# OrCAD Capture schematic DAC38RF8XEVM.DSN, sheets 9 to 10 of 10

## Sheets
9 SHEET 10 - POWER SUPPLIES: size B; title: POWER SUPPLIES
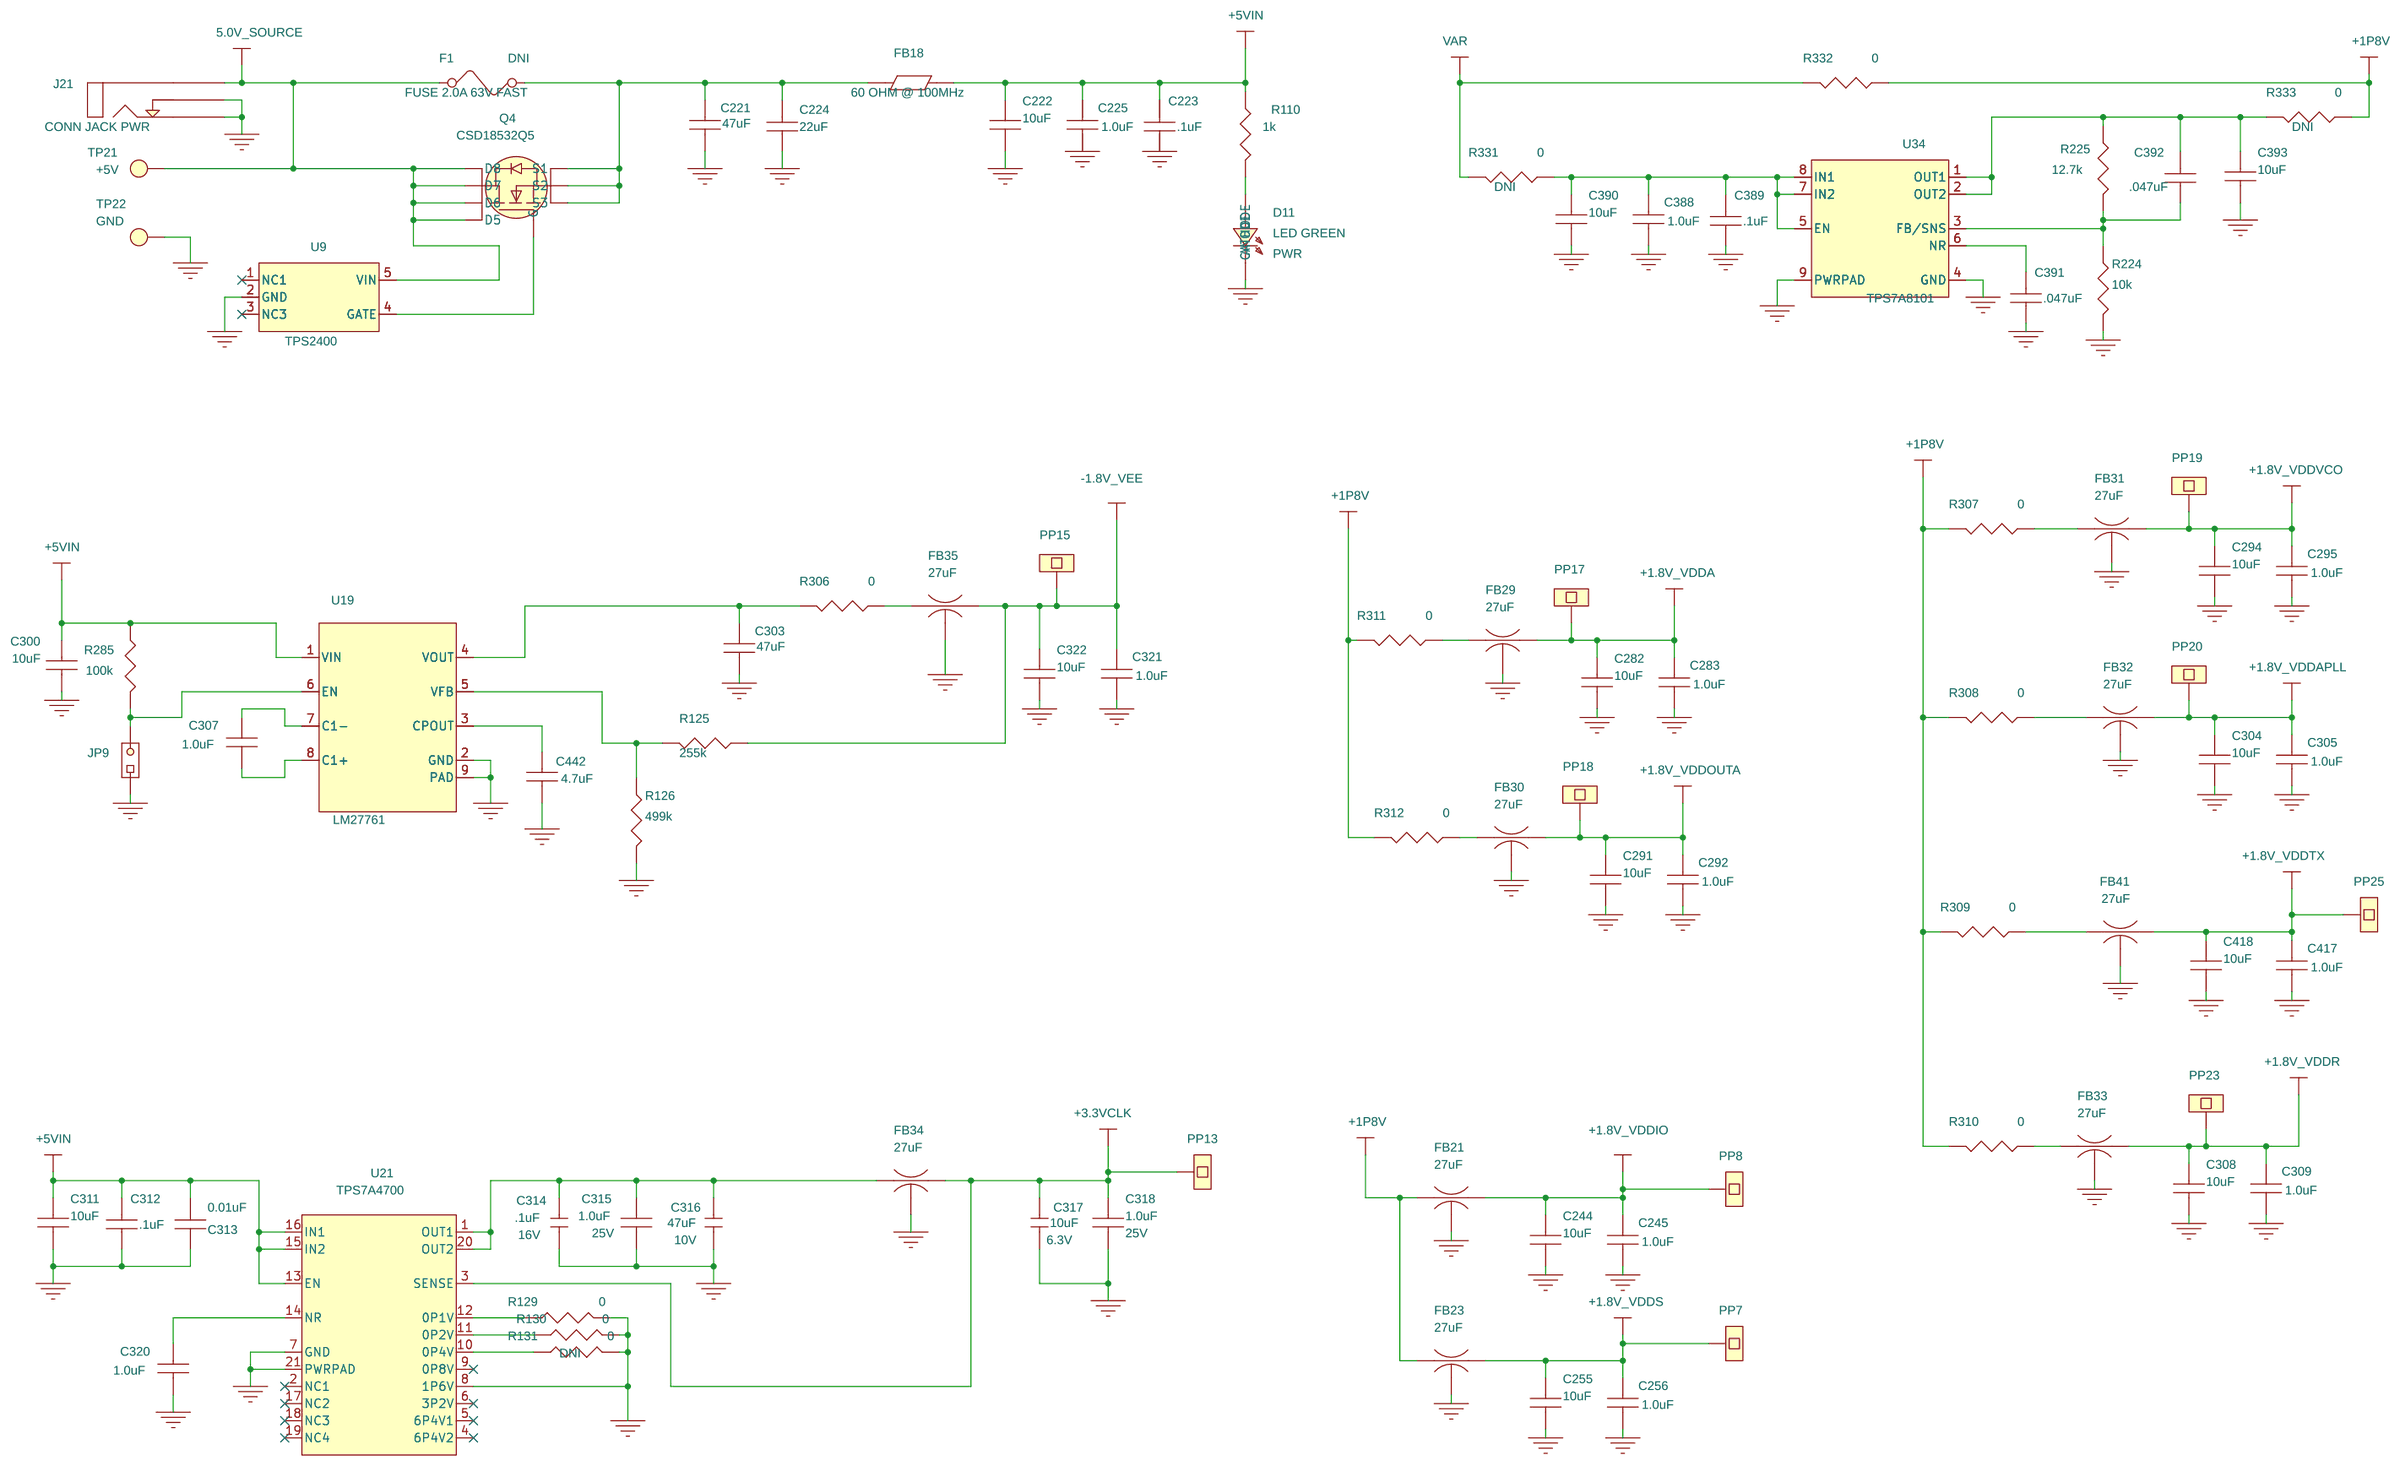
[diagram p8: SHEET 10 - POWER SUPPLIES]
10 SHEET 07 - USB I/F: size B; title: USB INTERFACE

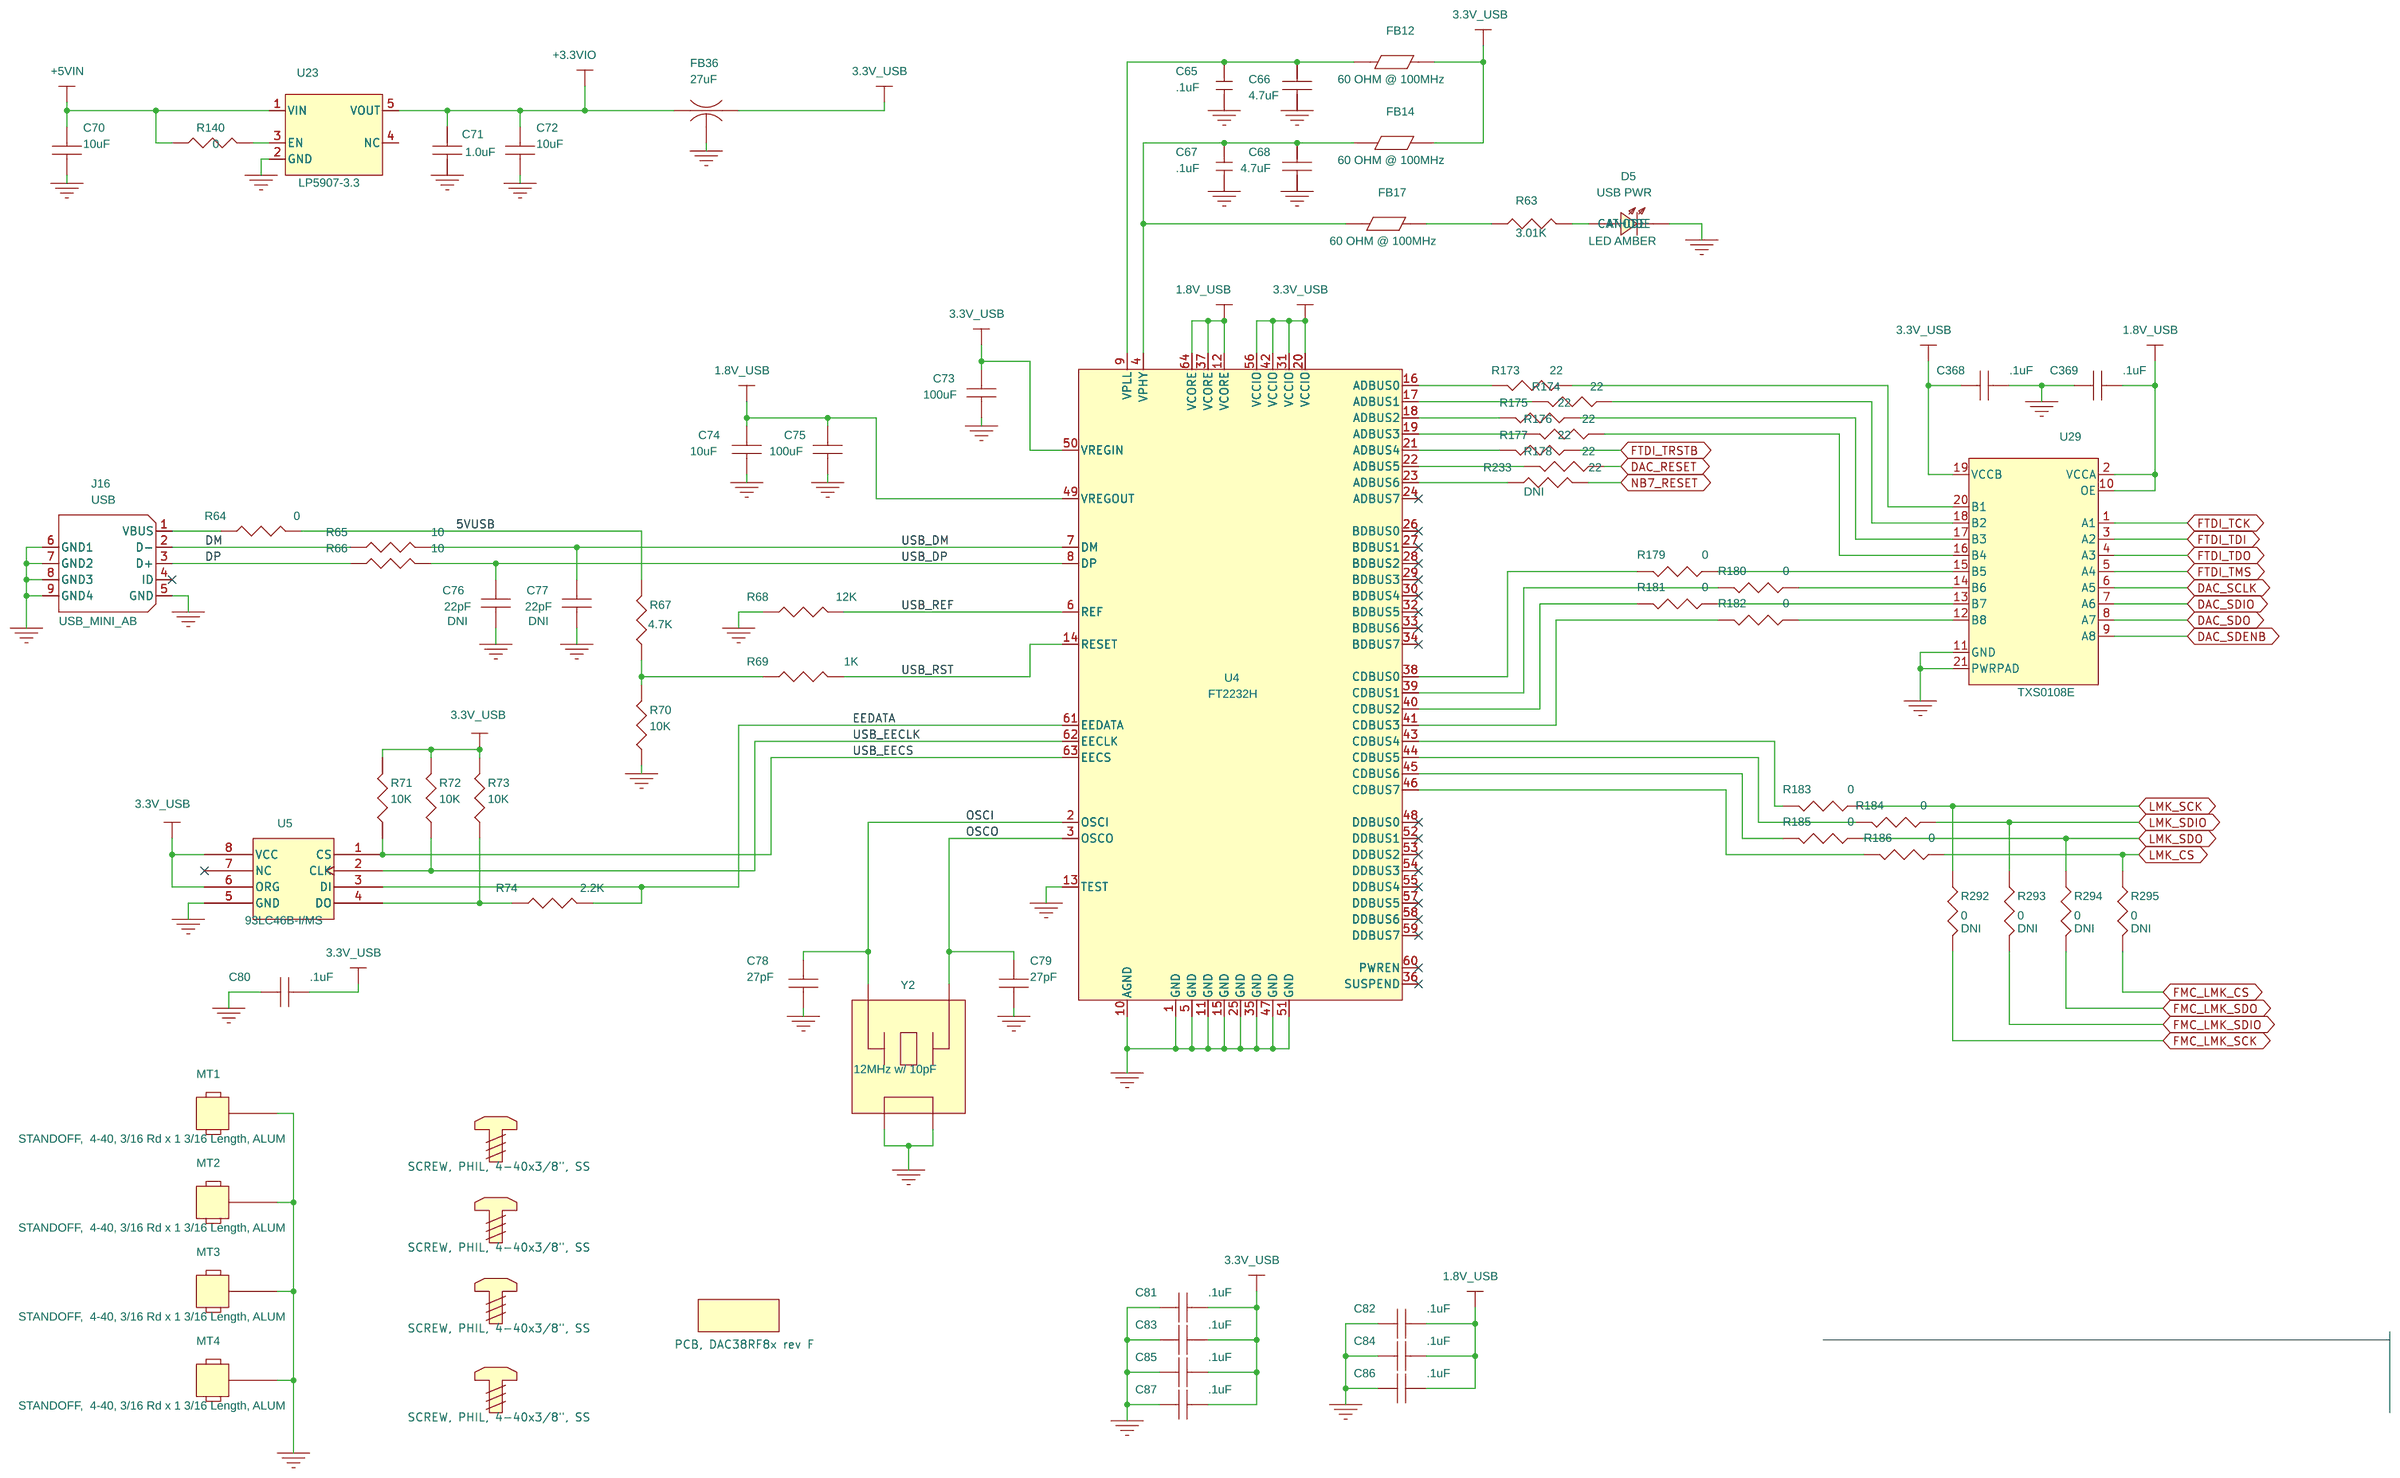
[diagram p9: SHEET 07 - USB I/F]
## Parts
sheet SHEET 07 - USB I/F
C65  .1uF  [0402]
C66  4.7uF  [0603]
C67  .1uF  [0402]
C68  4.7uF  [0603]
C70  10uF  [0805]
C71  1.0uF  [0603]
C72  10uF  [0805]
C73  100uF  [1206]
C74  10uF  [1206]
C75  100uF  [1206]
C76  22pF  [0402]
C77  22pF  [0402]
C78  27pF  [0402]
C79  27pF  [0402]
C80  .1uF  [0402]
C81  .1uF  [0402]
C82  .1uF  [0402]
C83  .1uF  [0402]
C84  .1uF  [0402]
C85  .1uF  [0402]
C86  .1uF  [0402]
C87  .1uF  [0402]
C368  .1uF  [0402]
C369  .1uF  [0402]
D5  LED AMBER  [LED_1206]
FB12  60 OHM @ 100MHz  [1206]
FB14  60 OHM @ 100MHz  [1206]
FB17  60 OHM @ 100MHz  [1206]
FB36  27uF  [1206_BEAD_NFM31P]
J16  USB_MINI_AB  [CON_SMRT_USBMINI_AB_F_mod]
MT1  STANDOFF,  4-40, 3/16 Rd x 1 3/16 Length, ALUM  [MFG125_PLATED]
MT2  STANDOFF,  4-40, 3/16 Rd x 1 3/16 Length, ALUM  [MFG125_PLATED]
MT3  STANDOFF,  4-40, 3/16 Rd x 1 3/16 Length, ALUM  [MFG125_PLATED]
MT4  STANDOFF,  4-40, 3/16 Rd x 1 3/16 Length, ALUM  [MFG125_PLATED]
R63  3.01K  [0402]
R64  0  [0603]
R65  10  [0402]
R66  10  [0402]
R67  4.7K  [0402]
R68  12K  [0402]
R69  1K  [0402]
R70  10K  [0402]
R71  10K  [0402]
R72  10K  [0402]
R73  10K  [0402]
R74  2.2K  [0402]
R140  0  [0402]
R173  22  [0402]
R174  22  [0402]
R175  22  [0402]
R176  22  [0402]
R177  22  [0402]
R178  22  [0402]
R179  0  [0402]
R180  0  [0402]
R181  0  [0402]
R182  0  [0402]
R183  0  [0402]
R184  0  [0402]
R185  0  [0402]
R186  0  [0402]
R233  22  [0402]
R292  0  [0402]
R293  0  [0402]
R294  0  [0402]
R295  0  [0402]
U4  FT2232H  [LQFP_64_402x402_20]
U5  93LC46B-I/MS  [MSOP_8_118X118_26]
U23  LP5907-3.3  [DBV5]
U29  TXS0108E  [QFN_20_183x144_RGY]
Y2  12MHz w/ 10pF  [XTAL_4_SM_130X102]
Z_BOARD1  PCB, DAC38RF8x rev F
Z_SCREW1  SCREW, PHIL, 4-40x3/8", SS
Z_SCREW2  SCREW, PHIL, 4-40x3/8", SS
Z_SCREW3  SCREW, PHIL, 4-40x3/8", SS
Z_SCREW4  SCREW, PHIL, 4-40x3/8", SS
sheet SHEET 10 - POWER SUPPLIES
C221  47uF  [1210]
C222  10uF  [0805]
C223  .1uF  [0402]
C224  22uF  [1206]
C225  1.0uF  [0603]
C244  10uF  [0805]
C245  1.0uF  [0603]
C255  10uF  [0805]
C256  1.0uF  [0603]
C282  10uF  [0805]
C283  1.0uF  [0603]
C291  10uF  [0805]
C292  1.0uF  [0603]
C294  10uF  [0805]
C295  1.0uF  [0603]
C300  10uF  [0805]
C303  47uF  [1210]
C304  10uF  [0805]
C305  1.0uF  [0603]
C307  1.0uF  [0603]
C308  10uF  [0805]
C309  1.0uF  [0603]
C311  10uF  [0805]
C312  .1uF  [0402]
C313  0.01uF  [0402]
C314  .1uF  [0402]
C315  1.0uF  [0603]
C316  47uF  [1210]
C317  10uF  [0805]
C318  1.0uF  [0603]
C320  1.0uF  [0603]
C321  1.0uF  [0603]
C322  10uF  [0805]
C388  1.0uF  [0603]
C389  .1uF  [0402]
C390  10uF  [0805]
C391  .047uF  [0402]
C392  .047uF  [0402]
C393  10uF  [0805]
C417  1.0uF  [0603]
C418  10uF  [0805]
C442  4.7uF  [0603]
D11  LED GREEN  [LED_1206]
F1  FUSE 2.0A 63V FAST  [1206]
FB18  60 OHM @ 100MHz  [1206]
FB21  27uF  [1206_BEAD_NFM31P]
FB23  27uF  [1206_BEAD_NFM31P]
FB29  27uF  [1206_BEAD_NFM31P]
FB30  27uF  [1206_BEAD_NFM31P]
FB31  27uF  [1206_BEAD_NFM31P]
FB32  27uF  [1206_BEAD_NFM31P]
FB33  27uF  [1206_BEAD_NFM31P]
FB34  27uF  [1206_BEAD_NFM31P]
FB35  27uF  [1206_BEAD_NFM31P]
FB41  27uF  [1206_BEAD_NFM31P]
J21  CONN JACK PWR  [CON_RAPC722_JACK_THVT_3]
JP9  HEADER_1x2_100_430L  [HDR_THVT_1x2_100_M]
PP7  PROBE POINT  [PROBE_POINT_22PAD]
PP8  PROBE POINT  [PROBE_POINT_22PAD]
PP13  PROBE POINT  [PROBE_POINT_22PAD]
PP15  PROBE POINT  [PROBE_POINT_22PAD]
PP17  PROBE POINT  [PROBE_POINT_22PAD]
PP18  PROBE POINT  [PROBE_POINT_22PAD]
PP19  PROBE POINT  [PROBE_POINT_22PAD]
PP20  PROBE POINT  [PROBE_POINT_22PAD]
PP23  PROBE POINT  [PROBE_POINT_22PAD]
PP25  PROBE POINT  [PROBE_POINT_22PAD]
Q4  CSD18532Q5  [SON_Q5B_8]
R110  1k  [0402]
R125  255k  [0402]
R126  499k  [0402]
R129  0  [0402]
R130  0  [0402]
R131  0  [0402]
R224  10k  [0402]
R225  12.7k  [0402]
R285  100k  [0402]
R306  0  [0805]
R307  0  [0805]
R308  0  [0805]
R309  0  [0805]
R310  0  [0805]
R311  0  [0805]
R312  0  [0805]
R331  0  [0805]
R332  0  [0805]
R333  0  [0805]
TP21  Testloop_Red  [testpoint_62dia]
TP22  Testloop_Black  [testpoint_62dia]
U9  TPS2400  [DBV5]
U19  LM27761  [SON_DSG_8]
U21  TPS7A4700  [qfn20_rgw_p65pitch]
U34  TPS7A8101  [SON_DRB_8]

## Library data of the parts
C65 C67 C314 = CAP0603: Mfr_Name: MURATA; Mfr_Part_Number: GRM155R71C104KA88D; TOL: 10%; Voltage: 16V
C66 C68 C442 = CAP_NP_0: Mfr_Name: Kemet; Mfr_Part_Number: C0603C475K8PACTU; TOL: 10%; VOLTAGE: 10V
C70 C72 C222 C244 C255 C282 C291 C294 C300 C304 C308 C322 C390 C393 C418 = CAP_NP_1: Mfr_Name: SAMSUNG; Mfr_Part_Number: CL21B106KOQNNNE; TOL: 10%; VOLTAGE: 16V
C71 C225 C307 C320 C388 = CAP_NP_0: Mfr_Name: TDK; Mfr_Part_Number: C1608X7R1E105K080AE; TOL: 10%; VOLTAGE: 25V
C73 C75 = CAP_1206: Mfr_Name: KEMET; Mfr_Part_Number: C1206C107M9PACTU
C74 = CAP_NP_1: CLASS: DISCRETE; Mfr_Name: MURATA; Mfr_Part_Number: GRM31CR61E106KA12L; TOL: 10%; VOLTAGE: 16V
C76 C77 = CAP_NP: Mfr_Name: AVX; Mfr_Part_Number: 04025A220KAT2A_DNI; Note: DNI; TOL: 10%; VOLTAGE: 50V
C78 C79 = CAP_NP: GROUP: NOT INSTALLED; Mfr_Name: Yageo; Mfr_Part_Number: CC0402JRNPO9BN270; TOL: 5%; VOLTAGE: 50V
C80-C87 C223 C312 C368 C369 C389 = CAPACITOR_NP_1: Mfr_Name: MURATA; Mfr_Part_Number: GRM155R71C104KA88D; TOL: 10%; Voltage: 16V
D5 = LED_AMBER_1206: TI_SILKTEXT: USB PWR
FB12 FB14 FB17 = FERRITE_BEAD: Mfr_Name: Taiyo Yuden; Mfr_Part_Number: FBMJ3216HM600-T; PART_NUMBER: Panasonic EXC-ML32A680U
FB36 = BEAD_NFM31P: Mfr_Name: Murata; Mfr_Part_Number: NFM31PC276B0J3; Tolerance: 20%
J16 = USB_MINI_AB_MNE20-5G5P10: Mfr_Name: Molex; Mfr_Part_Number: 678038020; TI_SILKTEXT: USB
MT1-MT4 = MOUNTING_HOLE: Mfr_Name: RAF Electronic Hardware; Mfr_Part_Number: 1648-440-AL
R63 = R: Mfr_Name: PANASONIC; Mfr_Part_Number: ERJ-2RKF3011X; TOL: 5%; VOLTAGE: 1/16W
R64 = Res_0402_Zero: Mfr_Name: PANASONIC; Mfr_Part_Number: ERJ-3GEY0R00V
R65 R66 = Res_0402_10_H
R67 = RESISTOR: 10K ohm, +/-1%, 1/16W(0402); Mfr_Name: PANASONIC; Mfr_Part_Number: ERJ-2RKF4701X; Package: SMD; Terasic_Prt: M0597; Type: Resistor
R68 = R: Mfr_Name: PANASONIC; Mfr_Part_Number: ERJ-2RKF1202X; TOL: 1%; Wattage: 1/16W
R69 = R_0: Mfr_Name: PANASONIC; Mfr_Part_Number: ERJ-2RKF1001X; TOL: 1%
R70-R73 = R_0: CLASS: DISCRETE; Mfr_Name: PANASONIC; Mfr_Part_Number: ERJ-2RKF1002X; TOL: 1%
R74 = RESISTOR: 2.2K ohm, +/-1%, 1/16W(0402); Mfr_Name: Yageo; Mfr_Part_Number: RC0402FR-072K2L; Package: SMD; Terasic_Prt: M0733; Type: Resistor
R129 R130 R140 = R: Mfr_Name: Panasonic; Mfr_Part_Number: ERJ-2GE0R00X; TOL: 5%
R173-R178 = Res_0402_10_H: Mfr_Part_Number: ERJ-2RKF22R0X
R179-R186 = Res_0402_10_H: Mfr_Part_Number: ERJ-2GE0R00X
R233 = Res_0603_Zero_H: Mfr_Part_Number: ERJ-2RKF22R0X; Note: DNI
R292-R295 = Res_0402_10_H: Mfr_Part_Number: ERJ-2GE0R00X; Note: DNI
U4 = FT4232H_2
U5 = EEPROM: 93LC46B-I/SN,Serial EEPROM, 64 x 16bit, 2.5V-5.5V; Mfr_Name: Microchip; Package: SMD; Terasic_Prt: M0252
U23 = LP5907: Mfr_Name: Texas Instruments; Mfr_Part_Number: LP5907MFX-3.3/NOPB
U29 = TXS0108E
Y2 = CRYSTAL1-4_SM: Mfr_Name: Abracon; Mfr_Part_Number: ABM8G-12.000MHZ-B4Y-T
Z_BOARD1 = BARE_BOARD: Mfr_Part_Number: DAC38RF8x rev F
Z_SCREW1-Z_SCREW4 = STANDOFF-SCREW
C221 C303 = CAP_NP_0: Mfr_Name: MURATA; Mfr_Part_Number: GRM32ER71A476KE15L; TOL: 10%; VOLTAGE: 10V
C224 = CAP_1210_22uF: Mfr_Name: MURATA; Mfr_Part_Number: GRM31CR71A226KE15L
C245 C256 C283 C292 C295 C305 C309 C321 C417 = CAP_NP_0: Mfr_Name: Samsung Electro-Mechanics America, Inc; Mfr_Part_Number: CL10B105KO8NNNC; TOL: 10%; VOLTAGE: 16V
C311 = CAP_NP_1: Mfr_Name: MURATA; Mfr_Part_Number: GRM21BR61E106KA73L; TOL: 10%; VOLTAGE: 25V
C313 = CAPACITOR_NP_1: Mfr_Name: MURATA; Mfr_Part_Number: GRM155R71H103KA88D; TOL: 10%; Voltage: 16V
C315 C318 = CAP_NP_1: Mfr_Name: TDK; Mfr_Part_Number: C1608X7R1E105K080AE; TOL: 10%; VOLTAGE: 25V
C316 = CAP0201_0: Mfr_Name: MURATA; Mfr_Part_Number: GRM32ER61A476KE20L; TOL: 10%; VOLTAGE: 10V
C317 = CAP0201_0: Mfr_Name: TDK; Mfr_Part_Number: C2012X5R0J106M125AB; TOL: 20%; VOLTAGE: 6.3V
C391 C392 = CAPACITOR_NP_1: Mfr_Name: MURATA; Mfr_Part_Number: GRM155R71E473KA88J; TOL: 10%; Voltage: 25V
D11 = LED_GREEN_1206: TI_SILKTEXT: PWR
F1 = FUSE_0: Mfr_Name: TE Connectivity; Mfr_Part_Number: 1206SFF200F/63-2; Note: DNI
FB18 = FERRITE_BEAD: Mfr_Name: Taiyo Yuden; Mfr_Part_Number: FBMJ3216HM600-T
FB21 FB23 FB29-FB35 FB41 = BEAD_NFM31P: Mfr_Name: Murata; Mfr_Part_Number: NFM31PC276B0J3L; Tolerance: 20%
J21 = CONN_JACK_PWR: Mfr_Name: SWITCHCRAFT; Mfr_Part_Number: RAPC722X
JP9 = JUMPER_1x2_0: TI_Silktext: <TI_Silktext>
PP7 = PROBE_POINT_0: TI_Silktext: +1.8V_VDDS
PP8 = PROBE_POINT_0: TI_Silktext: +1.8V_VDDIO
PP13 = PROBE_POINT_0: TI_Silktext: +3.3VCLK
PP15 = PROBE_POINT_0: TI_Silktext: -1.8V_VEE
PP17 = PROBE_POINT_0: TI_Silktext: +1.8V_VDDA
PP18 = PROBE_POINT_0: TI_Silktext: +1.8V_VDDOUT
PP19 = PROBE_POINT_0: TI_Silktext: +1.8V_VDDVCO
PP20 = PROBE_POINT_0: TI_Silktext: +1.8V_VDDAPLL
PP23 = PROBE_POINT_0: TI_Silktext: +1.8V_VDDR
PP25 = PROBE_POINT_0: TI_Silktext: +0.9V_VDDPLL
Q4 = CSD18532Q5B
R110 = Res_0402_1k
R125 = Res_0603_Zero_H: Mfr_Part_Number: ERJ-2RKF2553X
R126 = Res_0603_Zero_H: Mfr_Part_Number: ERJ-2RKF4993X
R131 = R: Mfr_Name: Panasonic; Mfr_Part_Number: ERJ-2GE0R00X; Note: DNI; TOL: 5%
R224 = R_1: CLASS: DISCRETE; Mfr_Name: Panasonic; Mfr_Part_Number: ERJ-2RKF1002X; TOL: 1%
R225 = R_1: CLASS: DISCRETE; Mfr_Name: Panasonic; Mfr_Part_Number: ERJ-2RKF1272X; TOL: 1%
R285 = R_1: CLASS: DISCRETE; Mfr_Name: PANASONIC; Mfr_Part_Number: ERJ-2RKF1003X; TOL: 1%; VOLTAGE: 1/10W
R306-R312 R332 = Res_0402_Zero_H_DNI: Mfr_Name: KEYSTONE; Mfr_Part_Number: 5106
R331 R333 = Res_0402_Zero_H_DNI: Mfr_Name: KEYSTONE; Mfr_Part_Number: 5106; Note: DNI
TP21 = TESTLOOP_BLACK: Mfr_Name: Keystone; Mfr_Part_Number: 5010; TI_SILKTEXT: +5V
TP22 = TESTLOOP_BLACK: Mfr_Name: KEYSTONE; Mfr_Part_Number: 5011; TI_SILKTEXT: GND
U9 = TPS2400: Mfr_Name: Texas Instruments; Mfr_Part_Number: TPS2400DBVT
U19 = LM27761: Mfr_Name: Texas Instruments; Mfr_Part_Number: LM27761DSGR
U21 = TPS7A4700: Mfr_Name: Texas Instruments; Mfr_Part_Number: TPS7A4700RGWT
U34 = TPS7A8101: Mfr_Name: Texas Instruments; Mfr_Part_Number: TPS7A8101DRBR

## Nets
1.8V_USB: C74.1 C75.1 C82.2 C84.2 C86.2 C369.2 U4.12(VCORE) U4.37(VCORE) U4.49(VREGOUT) U4.64(VCORE) U29.2(VCCA) U29.10(OE)
3.3V_USB: C73.1 C80.2 C81.2 C83.2 C85.2 C87.2 C368.1 FB12.1 FB14.1 FB36.3 R71.2 R72.2 R73.2 U4.20(VCCIO) U4.31(VCCIO) U4.42(VCCIO) U4.50(VREGIN) U4.56(VCCIO) U5.6(ORG) U5.8(VCC) U29.19(VCCB)
5.0V_SOURCE: F1.1 J21.1 Q4.5(D5) Q4.6(D6) Q4.7(D7) Q4.8(D8) TP21.1(TP) U9.5(VIN)
5VUSB: R64.1 R67.1
+1.8V_VDDA: C282.1 C283.1 FB29.3 PP17.1 ; also on sheet 2
+1.8V_VDDAPLL: C304.1 C305.1 FB32.3 PP20.1 ; also on sheet 2
+1.8V_VDDIO: C244.1 C245.1 FB21.3 PP8.1 ; also on sheet 1 2
+1.8V_VDDOUTA: C291.1 C292.1 FB30.3 PP18.1 ; also on sheet 2 3
+1.8V_VDDR: C308.1 C309.1 FB33.3 PP23.1 ; also on sheet 2
+1.8V_VDDS: C255.1 C256.1 FB23.3 PP7.1 ; also on sheet 2
+1.8V_VDDTX: C417.1 C418.1 FB41.1 PP25.1 ; also on sheet 2
+1.8V_VDDVCO: C294.1 C295.1 FB31.3 PP19.1 ; also on sheet 2
+3.3VCLK: C317.1 C318.1 FB34.3 PP13.1 U21.3(SENSE) ; also on sheet 4 5
+3.3VIO: C71.1 C72.1 FB36.1 U23.5(VOUT)
+5VIN: C70.1 C222.1 C223.2 C225.1 C300.1 C311.1 C312.2 C313.2 FB18.1 R110.1 R140.2 R285.1 U19.1(VIN) U21.13(EN) U21.15(IN2) U21.16(IN1) U23.1(VIN) ; also on sheet 7 8
-1.8V_VEE: C321.1 C322.1 FB35.3 PP15.1 R125.1 ; also on sheet 2
GND: C65.2 C66.2 C67.2 C68.2 C70.2 C71.2 C72.2 C73.2 C74.2 C75.2 C76.2 C77.2 C78.2 C79.2 C80.1 C81.1 C82.1 C83.1 C84.1 C85.1 C86.1 C87.1 C221.2 C222.2 C223.1 C224.1 C225.2 C244.2 C245.2 C255.2 C256.2 C282.2 C283.2 C291.2 C292.2 C294.2 C295.2 C300.2 C303.2 C304.2 C305.2 C308.2 C309.2 C311.2 C312.1 C313.1 C314.2 C315.2 C316.2 C317.2 C318.2 C320.2 C321.2 C322.2 C368.2 C369.1 C388.2 C389.1 C390.2 C391.1 C393.2 C417.2 C418.2 C442.2 D5.2(CATHODE) D11.2(CATHODE) FB21.2 FB23.2 FB29.2 FB30.2 FB31.2 FB32.2 FB33.2 FB34.2 FB35.2 FB36.2 FB41.2 J16.5(GND) J16.6(GND1) J16.7(GND2) J16.8(GND3) J16.9(GND4) J21.2 J21.3 JP9.1 MT1.1 MT2.1 MT3.1 MT4.1 R68.2 R70.1 R126.1 R129.1 R130.1 R131.1 R224.1 TP22.1(TP) U4.1(GND) U4.5(GND) U4.10(AGND) U4.11(GND) U4.13(TEST) U4.15(GND) U4.25(GND) U4.35(GND) U4.47(GND) U4.51(GND) U5.5(GND) U9.2(GND) U19.2(GND) U19.9(PAD) U21.7(GND) U21.8(1P6V) U21.21(PWRPAD) U23.2(GND) U29.11(GND) U29.21(PWRPAD) U34.4(GND) U34.9(PWRPAD) Y2.2 Y2.4 ; also on sheet 1 2 3 4 5 7 8
+1P8V: FB21.1 FB23.1 R307.2 R308.2 R309.2 R310.2 R311.2 R312.2 R332.1 R333.1
DAC_RESET: R178.1 ; also on sheet 1
DAC_SCLK: U29.6(A5) ; also on sheet 1
DAC_SDENB: U29.9(A8) ; also on sheet 1
DAC_SDIO: U29.7(A6) ; also on sheet 1
DAC_SDO: U29.8(A7) ; also on sheet 1
DM: J16.2(D-) R65.1
DP: J16.3(D+) R66.1
EEDATA: R74.1 U4.61(EEDATA) U5.3(DI)
FMC_LMK_CS: R295.2 ; also on sheet 7
FMC_LMK_SCK: R292.2 ; also on sheet 7
FMC_LMK_SDIO: R293.2 ; also on sheet 7
FMC_LMK_SDO: R294.2 ; also on sheet 7
FTDI_TCK: U29.1(A1) ; also on sheet 1
FTDI_TDI: U29.3(A2) ; also on sheet 1
FTDI_TDO: U29.4(A3) ; also on sheet 1
FTDI_TMS: U29.5(A4) ; also on sheet 1
FTDI_TRSTB: R177.1 ; also on sheet 1
LMK_CS: R186.1 R295.1 ; also on sheet 5
LMK_SCK: R183.1 R292.1 ; also on sheet 5
LMK_SDIO: R184.1 R293.1 ; also on sheet 5
LMK_SDO: R185.1 R294.1 ; also on sheet 5
NB7_RESET: R233.2 ; also on sheet 1 4 7
OSCI: C78.1 U4.2(OSCI) Y2.1
OSCO: C79.1 U4.3(OSCO) Y2.3
USB_DM: C77.1 R65.2 U4.7(DM)
USB_DP: C76.1 R66.2 U4.8(DP)
USB_EECLK: R72.1 U4.62(EECLK) U5.2(CLK)
USB_EECS: R71.1 U4.63(EECS) U5.1(CS)
USB_REF: R68.1 U4.6(REF)
USB_RST: R69.2 U4.14(RESET)
VAR: R331.2 R332.2 ; also on sheet 8
N16791764: J16.1(VBUS) R64.2
N16791900: C67.1 C68.1 FB14.2 FB17.2 U4.4(VPHY)
N16791904: C65.1 C66.1 FB12.2 U4.9(VPLL)
N16792068: R67.2 R69.1 R70.2
N16792392: R73.1 R74.2 U5.4(DO)
N16935208: R178.2 U4.22(ADBUS5)
N16935212: R177.2 U4.21(ADBUS4)
N16935236: R174.2 U4.17(ADBUS1)
N16935238: R176.2 U4.19(ADBUS3)
N16935240: R173.2 U4.16(ADBUS0)
N16935242: R175.2 U4.18(ADBUS2)
N17033323: FB17.1 R63.1
N17033325: D5.1(ANODE) R63.2
N17785139: R125.2 R126.2 U19.5(VFB)
N17785180: C303.1 R306.2 U19.4(VOUT)
N17787232: C314.1 C315.1 C316.1 FB34.1 U21.1(OUT1) U21.20(OUT2)
N17787234: C320.1 U21.14(NR)
N17787274: R129.2 U21.12(0P1V)
N17787303: R130.2 U21.11(0P2V)
N17787374: R131.2 U21.10(0P4V)
N17829143: R140.1 U23.3(EN)
N18051729: R179.2 U4.38(CDBUS0)
N18051775: R180.2 U4.39(CDBUS1)
N18051825: R181.2 U4.40(CDBUS2)
N18051839: R182.2 U4.41(CDBUS3)
N18096853: R173.1 U29.20(B1)
N18096873: R174.1 U29.18(B2)
N18096893: R175.1 U29.17(B3)
N18096913: R176.1 U29.16(B4)
N18127566: R179.1 U29.15(B5)
N18127584: R180.1 U29.14(B6)
N18127610: R181.1 U29.13(B7)
N18127628: R182.1 U29.12(B8)
N18304202: C388.1 C389.2 C390.1 R331.1 U34.5(EN) U34.7(IN2) U34.8(IN1)
N18304279: C392.1 R224.2 R225.1 U34.3(FB/SNS)
N18304291: C391.2 U34.6(NR)
N18304307: C392.2 C393.1 R225.2 R333.2 U34.1(OUT1) U34.2(OUT2)
N18332757: R233.1 U4.23(ADBUS6)
N18554997: D11.1(ANODE) R110.2
N18555017: C221.1 C224.2 F1.2 FB18.2 Q4.1(S1) Q4.2(S2) Q4.3(S3)
N18555159: Q4.4(G) U9.4(GATE)
N18691780: C307.1 U19.7(C1-)
N18691785: C307.2 U19.8(C1+)
N18692860: C442.1 U19.3(CPOUT)
N18693421: JP9.2 R285.2 U19.6(EN)
N18716152: R183.2 U4.43(CDBUS4)
N18716161: R184.2 U4.44(CDBUS5)
N18716170: R185.2 U4.45(CDBUS6)
N18716191: R186.2 U4.46(CDBUS7)
N18728685: FB35.1 R306.1
N18728712: FB31.1 R307.1
N18728940: FB32.1 R308.1
N18728990: FB41.3 R309.1
N18729042: FB33.1 R310.1
N18729096: FB29.1 R311.1
N18729152: FB30.1 R312.1

Not connected (* = marked no-connect by the designer): J16 4(ID)*; U4 24(ADBUS7)* 26(BDBUS0)* 27(BDBUS1)* 28(BDBUS2)* 29(BDBUS3)* 30(BDBUS4)* 32(BDBUS5)* 33(BDBUS6)* 34(BDBUS7)* 36(SUSPEND)* 48(DDBUS0)* 52(DDBUS1)* 53(DDBUS2)* 54(DDBUS3)* 55(DDBUS4)* 57(DDBUS5)* 58(DDBUS6)* 59(DDBUS7)* 60(PWREN)*; U5 7(NC)*; U9 1(NC1)* 3(NC3)*; U21 2(NC1)* 4(6P4V2)* 5(6P4V1)* 6(3P2V)* 9(0P8V)* 17(NC2)* 18(NC3)* 19(NC4)*; U23 4(NC)
